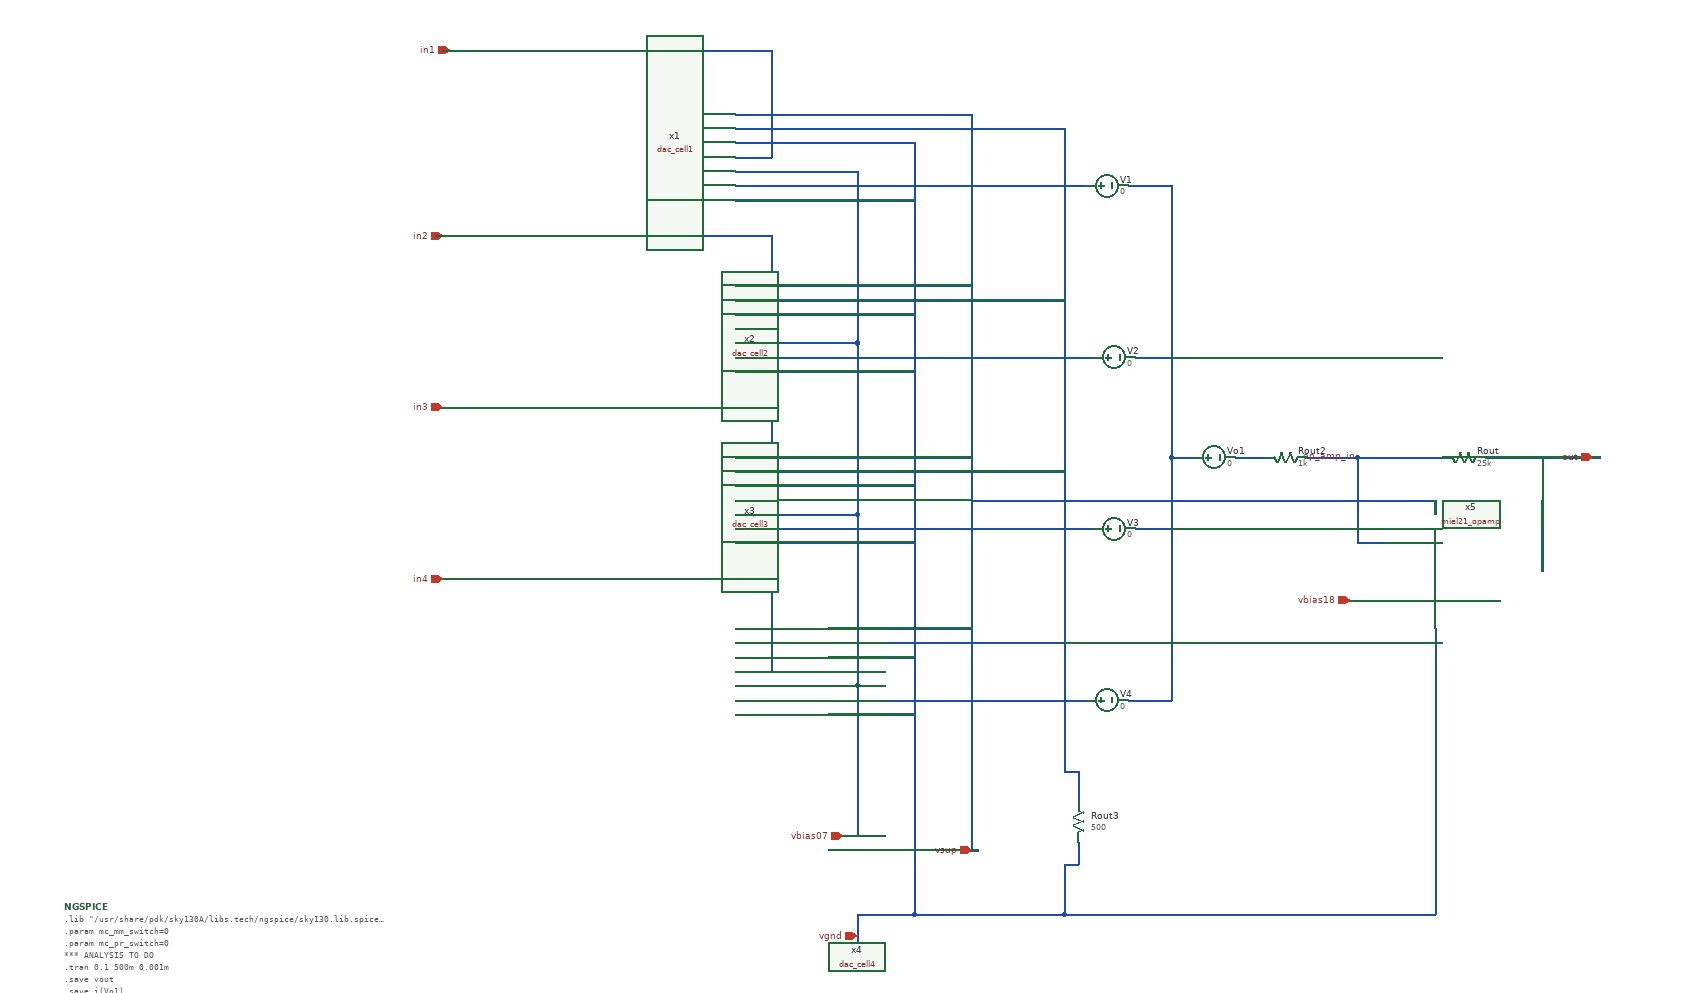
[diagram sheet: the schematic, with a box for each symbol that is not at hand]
v {xschem version=2.9.9 file_version=1.2 }
G {}
K {}
V {}
S {}
E {}
N 1600 -1150 1600 -940 { lab=vbias07}
N 1430 -1150 1600 -1150 { lab=vbias07}
N 1430 -1390 1600 -1390 { lab=vbias07}
N 1600 -1390 1600 -1150 { lab=vbias07}
N 1600 -1630 1600 -1390 { lab=vbias07}
N 1430 -1630 1600 -1630 { lab=vbias07}
N 1600 -1860 1600 -1630 { lab=vbias07}
N 1600 -1870 1600 -1860 { lab=vbias07}
N 1430 -1870 1600 -1870 { lab=vbias07}
N 1600 -830 1680 -830 { lab=vgnd}
N 1680 -1890 1680 -830 { lab=vgnd}
N 1430 -1910 1680 -1910 { lab=vgnd}
N 1680 -1910 1680 -1890 { lab=vgnd}
N 1430 -1670 1680 -1670 { lab=vgnd}
N 1430 -1430 1680 -1430 { lab=vgnd}
N 1430 -1190 1680 -1190 { lab=vgnd}
N 1680 -830 1760 -830 { lab=vgnd}
N 1760 -1950 1760 -940 { lab=vsup}
N 1430 -1950 1760 -1950 { lab=vsup}
N 1430 -1710 1760 -1710 { lab=vsup}
N 1430 -1470 1760 -1470 { lab=vsup}
N 1430 -1230 1760 -1230 { lab=vsup}
N 1890 -880 1890 -830 { lab=vgnd}
N 1760 -830 1890 -830 { lab=vgnd}
N 1430 -1930 1890 -1930 { lab=#net1}
N 1430 -1690 1890 -1690 { lab=#net1}
N 1430 -1450 1890 -1450 { lab=#net1}
N 1430 -1210 1890 -1210 { lab=#net1}
N 2480 -1470 2620 -1470 { lab=out}
N 1480 -2000 1480 -1890 { lab=in1}
N 1430 -1890 1480 -1890 { lab=in1}
N 1480 -1760 1480 -1650 { lab=in2}
N 1430 -1650 1480 -1650 { lab=in2}
N 1480 -1520 1480 -1410 { lab=in3}
N 1430 -1410 1480 -1410 { lab=in3}
N 1480 -1280 1480 -1170 { lab=in4}
N 1430 -1170 1480 -1170 { lab=in4}
N 1480 -2040 1480 -2000 { lab=in1}
N 1030 -2040 1480 -2040 { lab=in1}
N 1030 -1780 1480 -1780 { lab=in2}
N 1480 -1780 1480 -1760 { lab=in2}
N 1030 -1540 1480 -1540 { lab=in3}
N 1480 -1540 1480 -1520 { lab=in3}
N 1030 -1300 1480 -1300 { lab=in4}
N 1480 -1300 1480 -1280 { lab=in4}
N 2040 -1820 2040 -1470 { lab=#net2}
N 2040 -1470 2040 -1350 { lab=#net2}
N 2040 -1850 2040 -1820 { lab=#net2}
N 2410 -1230 2410 -1210 { lab=vgnd}
N 2410 -1210 2410 -1160 { lab=vgnd}
N 2040 -1350 2040 -1130 { lab=#net2}
N 2300 -1470 2340 -1470 { lab=op_amp_in}
N 2400 -1470 2420 -1470 { lab=op_amp_in}
N 1980 -1850 2040 -1850 { lab=#net2}
N 1990 -1610 2040 -1610 { lab=#net2}
N 1990 -1370 2040 -1370 { lab=#net2}
N 1980 -1130 2040 -1130 { lab=#net2}
N 2040 -1470 2060 -1470 { lab=#net2}
N 2340 -1470 2400 -1470 { lab=op_amp_in}
N 1900 -1610 1930 -1610 { lab=#net3}
N 2560 -1470 2560 -1310 { lab=out}
N 2300 -1350 2340 -1350 { lab=op_amp_in}
N 2300 -1270 2340 -1270 { lab=vbias18}
N 1900 -1370 1930 -1370 { lab=#net4}
N 1900 -1130 1920 -1130 { lab=#net5}
N 1910 -1850 1920 -1850 { lab=#net6}
N 2300 -1470 2300 -1350 { lab=op_amp_in}
N 2060 -1470 2070 -1470 { lab=#net2}
N 1900 -1850 1910 -1850 { lab=#net6}
N 2130 -1470 2170 -1470 { lab=#net7}
N 2230 -1470 2300 -1470 { lab=op_amp_in}
N 1430 -1850 1900 -1850 { lab=#net6}
N 1430 -1830 1680 -1830 { lab=vgnd}
N 1430 -1610 1900 -1610 { lab=#net3}
N 1430 -1590 1680 -1590 { lab=vgnd}
N 1430 -1370 1900 -1370 { lab=#net4}
N 1430 -1350 1680 -1350 { lab=vgnd}
N 1430 -1130 1900 -1130 { lab=#net5}
N 1430 -1110 1680 -1110 { lab=vgnd}
N 1910 -1030 1910 -990 { lab=#net1}
N 1890 -1030 1910 -1030 { lab=#net1}
N 1910 -930 1910 -900 { lab=vgnd}
N 1890 -900 1910 -900 { lab=vgnd}
N 1890 -900 1890 -880 { lab=vgnd}
N 1890 -1930 1890 -1030 { lab=#net1}
N 1020 -2040 1030 -2040 { lab=in1}
N 1010 -1780 1030 -1780 { lab=in2}
N 1010 -1540 1030 -1540 { lab=in3}
N 1010 -1300 1030 -1300 { lab=in4}
N 1570 -940 1600 -940 { lab=vbias07}
N 1600 -810 1600 -790 { lab=vgnd}
N 1600 -830 1600 -810 { lab=vgnd}
N 1760 -940 1760 -920 { lab=vsup}
N 1760 -920 1770 -920 { lab=vsup}
N 2620 -1470 2640 -1470 { lab=out}
N 2410 -1160 2410 -1140 { lab=vgnd}
N 2280 -1270 2300 -1270 { lab=vbias18}
N 1890 -830 2410 -830 { lab=vgnd}
N 2410 -1140 2410 -830 { lab=vgnd}
N 1760 -1410 2410 -1410 { lab=vsup}
N 2410 -1410 2410 -1390 { lab=vsup}
C {/opt/uniccass/dev/dac_cell2/tb/dac_cell2.sym} 1280 -1650 0 0 {name=x2}
C {/opt/uniccass/dev/dac_cell3/tb/dac_cell3.sym} 1280 -1410 0 0 {name=x3}
C {/opt/uniccass/dev/dac_cell4/tb/dac_cell4.sym} 1280 -1170 0 0 {name=x4}
C {devices/res.sym} 2450 -1470 1 0 {name=Rout
value=25k
footprint=1206
device=resistor
m=1}
C {devices/lab_wire.sym} 2300 -1470 1 0 {name=l2 sig_type=std_logic lab=op_amp_in}
C {devices/code_shown.sym} 490 -840 0 0 {name=NGSPICE
only_toplevel=true
value="
.lib \\"/usr/share/pdk/sky130A/libs.tech/ngspice/sky130.lib.spice\\" tt
.param mc_mm_switch=0
.param mc_pr_switch=0
*** ANALYSIS TO DO

.tran 0.1 500m 0.001m
.save vout
.save i(Vo1)
.save i(V1)
.save i(V2)
.save i(V3)
.save i(V4)
.save i(V5)
.save op_amp_in
.save output
.save vsw1 vsw2 vsw3 vsw4

.control
set wr_vecnames
set wr_singlescale

run
******** results filename  ************ nodes to write
wrdata $DEV_PATH/res/dac_top_cell_with_opamp_vout_tran_vol.res vout
wrdata $DEV_PATH/res/dac_top_cell_with_opamp_vsw1_tran_vol.res vsw1
wrdata $DEV_PATH/res/dac_top_cell_with_opamp_vsw2_tran_vol.res vsw2
wrdata $DEV_PATH/res/dac_top_cell_with_opamp_vsw3_tran_vol.res vsw3
wrdata $DEV_PATH/res/dac_top_cell_with_opamp_vsw4_tran_vol.res vsw4
.endc
"}
C {/opt/uniccass/dev/opamp/miel21_opamp.sym} 2490 -1310 0 0 {name=x5}
C {devices/vsource.sym} 1950 -1850 3 0 {name=V1 value=0}
C {devices/vsource.sym} 1960 -1610 3 0 {name=V2 value=0}
C {devices/vsource.sym} 1960 -1370 3 0 {name=V3 value=0}
C {devices/vsource.sym} 1950 -1130 3 0 {name=V4 value=0}
C {devices/vsource.sym} 2100 -1470 3 0 {name=Vo1 value=0}
C {devices/res.sym} 2200 -1470 1 0 {name=Rout2
value=1k
footprint=1206
device=resistor
m=1}
C {devices/res.sym} 1910 -960 0 0 {name=Rout3
value=500
footprint=1206
device=resistor
m=1}
C {devices/iopin.sym} 1030 -2040 2 0 {name=p1 lab=in1}
C {devices/iopin.sym} 1020 -1780 2 0 {name=p2 lab=in2}
C {devices/iopin.sym} 1020 -1540 2 0 {name=p3 lab=in3}
C {devices/iopin.sym} 1020 -1300 2 0 {name=p4 lab=in4}
C {devices/iopin.sym} 1580 -940 2 0 {name=p5 lab=vbias07}
C {devices/iopin.sym} 1600 -800 1 0 {name=p6 lab=vgnd}
C {devices/iopin.sym} 1760 -920 0 0 {name=p7 lab=vsup}
C {devices/iopin.sym} 2630 -1470 0 0 {name=p9 lab=out}
C {devices/iopin.sym} 2290 -1270 2 0 {name=p11 lab=vbias18}
C {/opt/uniccass/dev/dac_cell1/tb/dac_cell1.sym} 1280 -1890 0 0 {name=x1}
